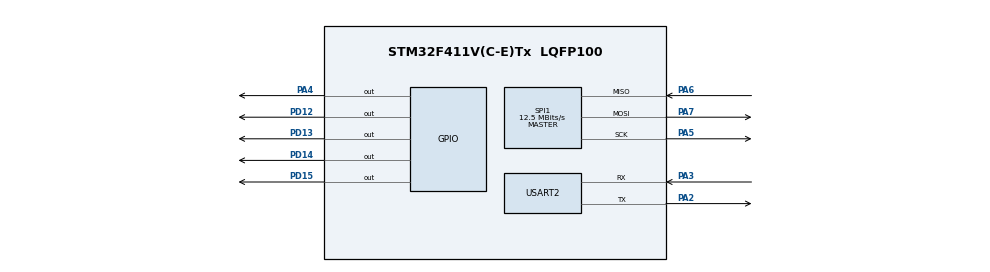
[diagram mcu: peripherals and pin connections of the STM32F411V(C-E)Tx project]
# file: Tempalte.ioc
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Mcu.Family=STM32F4
Mcu.Name=STM32F411V(C-E)Tx
Mcu.Package=LQFP100
NVIC.PriorityGroup=NVIC_PRIORITYGROUP_4
PA2.Mode=Asynchronous
PA2.Signal=USART2_TX
PA3.Mode=Asynchronous
PA3.Signal=USART2_RX
PA4.Signal=GPIO_Output
PA5.Mode=Full_Duplex_Master
PA5.Signal=SPI1_SCK
PA6.Mode=Full_Duplex_Master
PA6.Signal=SPI1_MISO
PA7.Mode=Full_Duplex_Master
PA7.Signal=SPI1_MOSI
PD12.Signal=GPIO_Output
PD13.Signal=GPIO_Output
PD14.Signal=GPIO_Output
PD15.Signal=GPIO_Output
PH0\ -\ OSC_IN.Mode=HSE-External-Oscillator
PH0\ -\ OSC_IN.Signal=RCC_OSC_IN
PH1\ -\ OSC_OUT.Mode=HSE-External-Oscillator
PH1\ -\ OSC_OUT.Signal=RCC_OSC_OUT
ProjectManager.HeapSize=0x200
ProjectManager.StackSize=0x400
ProjectManager.TargetToolchain=Makefile
RCC.AHBFreq_Value=25000000
RCC.APB1Freq_Value=25000000
RCC.APB1TimFreq_Value=25000000
RCC.APB2Freq_Value=25000000
RCC.APB2TimFreq_Value=25000000
RCC.CortexFreq_Value=25000000
RCC.HCLKFreq_Value=25000000
RCC.HSE_VALUE=25000000
RCC.HSI_VALUE=16000000
RCC.LSE_VALUE=32768
RCC.SYSCLKFreq_VALUE=25000000
RCC.SYSCLKSource=RCC_SYSCLKSOURCE_HSE
RCC.VCOOutputFreq_Value=192000000
SPI1.CalculateBaudRate=12.5 MBits/s
SPI1.Direction=SPI_DIRECTION_2LINES
SPI1.Mode=SPI_MODE_MASTER
SPI1.VirtualType=VM_MASTER
USART2.VirtualMode=VM_ASYNC
board=custom

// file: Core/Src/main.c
/* USER CODE BEGIN Header */
/**
  ******************************************************************************
  * @file           : main.c
  * @brief          : STM32F411 Discovery Onboard Gyroscope SPI1 Test
  ******************************************************************************
  */
/* USER CODE END Header */

#include "main.h"
#include "stdlib.h"

SPI_HandleTypeDef hspi1;
UART_HandleTypeDef huart2;

/* Macro điều khiển chân Chip Select (CS) của Gyro onboard (PE3) */
#define TEST 1

void SystemClock_Config(void);
static void MX_GPIO_Init(void);
static void MX_SPI1_Init(void);
static void MX_USART2_UART_Init(void);

void UART_PrintChar(char c);
void UART_PrintStr(const char *str);
void UART_PrintHex(uint8_t num);

uint8_t flag_exti0 = 0;
volatile uint16_t exti_pin = 0;
uint8_t  flag_exti = 0;

void EXTI0_IRQHandler(void) {

   HAL_GPIO_EXTI_IRQHandler(GPIO_PIN_0);
   UART_PrintStr("\r\n=======EXTI0_IRQHandler Complete=======\r\n");
   UART_PrintStr("\r\n=======Flag = {");
   UART_PrintChar(flag_exti0);
   UART_PrintStr("}---\r\n");

}

void HAL_GPIO_EXTI_Callback(uint16_t GPIO_Pin)
{
  UNUSED(GPIO_Pin);

  exti_pin  = GPIO_Pin;
  flag_exti = 1;
  if (GPIO_Pin == GPIO_PIN_0) {
      if(!flag_exti0)
        flag_exti0 = 1;
  }

}

void Init_EXTI0_ButtonUser(void) {
  GPIO_InitTypeDef gpio = {0};
  __HAL_RCC_GPIOA_CLK_ENABLE();
  gpio.Mode = GPIO_MODE_IT_RISING;
  gpio.Pull = GPIO_NOPULL;

  gpio.Pin = GPIO_PIN_0;                 // Discovery / Black Pill
  HAL_GPIO_Init(GPIOA, &gpio);

  HAL_NVIC_SetPriority(EXTI0_IRQn, 2, 0);
  HAL_NVIC_EnableIRQ(EXTI0_IRQn);
}

void SPI1_IRQHandler(void) {
  HAL_SPI_IRQHandler(&hspi1);
}

void HAL_SPI_ErrorCallback(SPI_HandleTypeDef *hspi) {
  UART_PrintStr("\r\n=======SPI ERROR=======\r\n");
}

static void DumpClockSystemAndSyTick() {

  printf("Clock System = %d\n", SystemCoreClock);
  printf("Frequence of systick = ");
  switch (HAL_GetTickFreq())
  {
  case HAL_TICK_FREQ_10HZ:
    printf("10HZ => T = 0,1s \n");
    break;
  case HAL_TICK_FREQ_100HZ:
    printf("100HZ => T = 0,01s \n");
    break;
  case HAL_TICK_FREQ_1KHZ:
    printf("1000HZ => T = 1ms \n");
    break;
  default:
    break;
  }
}

int main(void)
{
  /* Khởi tạo hệ thống HAL, Clock và Peripherals */
  HAL_Init();
  SystemClock_Config();
  MX_GPIO_Init();
  MX_SPI1_Init();
  MX_USART2_UART_Init();
  HAL_Delay(200);
  Init_EXTI0_ButtonUser();
  UART_PrintStr("\033[2J\033[H"); // Clear terminal

  UART_PrintStr("\r\n==================================\r\n");
  UART_PrintStr("  STM32F411 INIT    \r\n");
  UART_PrintStr("==================================\r\n");
  DumpClockSystemAndSyTick();
  uint16_t current_tick = HAL_GetTick();
  printf("First Systick = %d\n", current_tick);
  while (HAL_GetTick() - current_tick < 1000);
  printf("End Systick = %d\n", HAL_GetTick());

  UART_PrintStr("\r\n==================================\r\n");
  UART_PrintStr("  STM32F411 DISCOVERY SPI TEST    \r\n");
  UART_PrintStr("==================================\r\n");

#if(TEST)
  Read_Gyro_WHO_AM_I();
  TC_Write_Single_mode_CTRL_REG3_22H();
  TC_Write_Mul_Mode_CTRL_REG1_20H_21H();
  TC_Read_Mul_Mode_CTRL_REG1_20H_21H();
#endif
  /* Vòng lặp chính */
  int count = 10U;
  while (1)
  {

  }
}

void SystemClock_Config(void)
{
  RCC_OscInitTypeDef RCC_OscInitStruct = {0};
  RCC_ClkInitTypeDef RCC_ClkInitStruct = {0};

  __HAL_RCC_PWR_CLK_ENABLE();
  __HAL_PWR_VOLTAGESCALING_CONFIG(PWR_REGULATOR_VOLTAGE_SCALE1);

  RCC_OscInitStruct.OscillatorType = RCC_OSCILLATORTYPE_HSI;
  RCC_OscInitStruct.HSIState = RCC_HSI_ON;
  RCC_OscInitStruct.HSICalibrationValue = RCC_HSICALIBRATION_DEFAULT;
  RCC_OscInitStruct.PLL.PLLState = RCC_PLL_NONE;
  if (HAL_RCC_OscConfig(&RCC_OscInitStruct) != HAL_OK)
  {
    Error_Handler();
  }

  RCC_ClkInitStruct.ClockType = RCC_CLOCKTYPE_HCLK | RCC_CLOCKTYPE_SYSCLK
                              | RCC_CLOCKTYPE_PCLK1 | RCC_CLOCKTYPE_PCLK2;
  RCC_ClkInitStruct.SYSCLKSource = RCC_SYSCLKSOURCE_HSI;
  RCC_ClkInitStruct.AHBCLKDivider = RCC_SYSCLK_DIV1;
  RCC_ClkInitStruct.APB1CLKDivider = RCC_HCLK_DIV1;
  RCC_ClkInitStruct.APB2CLKDivider = RCC_HCLK_DIV1;

  if (HAL_RCC_ClockConfig(&RCC_ClkInitStruct, FLASH_LATENCY_0) != HAL_OK)
  {
    Error_Handler();
  }
}

static void MX_SPI1_Init(void)
{
  __HAL_RCC_SPI1_CLK_ENABLE();

  hspi1.Instance = SPI1;
  hspi1.Init.Mode = SPI_MODE_MASTER;
  hspi1.Init.Direction = SPI_DIRECTION_2LINES;
  hspi1.Init.DataSize = SPI_DATASIZE_8BIT;

  /* Cấu hình SPI Mode 3 (CPOL High, CPHA 2Edge) cho L3GD20 */
  hspi1.Init.CLKPolarity = SPI_POLARITY_HIGH;
  hspi1.Init.CLKPhase = SPI_PHASE_2EDGE;

  hspi1.Init.NSS = SPI_NSS_SOFT;
  hspi1.Init.BaudRatePrescaler = SPI_BAUDRATEPRESCALER_8; // Baudrate ~2MHz
  hspi1.Init.FirstBit = SPI_FIRSTBIT_MSB;
  hspi1.Init.TIMode = SPI_TIMODE_DISABLE;
  hspi1.Init.CRCCalculation = SPI_CRCCALCULATION_DISABLE;
  hspi1.Init.CRCPolynomial = 10;

  if (HAL_SPI_Init(&hspi1) != HAL_OK)
  {
    Error_Handler();
  }

  HAL_NVIC_SetPriority(SPI1_IRQn, 3, 0);
  HAL_NVIC_EnableIRQ(SPI1_IRQn);
}

static void MX_USART2_UART_Init(void)
{
  __HAL_RCC_USART2_CLK_ENABLE();

  huart2.Instance = USART2;
  huart2.Init.BaudRate = 115200;
  huart2.Init.WordLength = UART_WORDLENGTH_8B;
  huart2.Init.StopBits = UART_STOPBITS_1;
  huart2.Init.Parity = UART_PARITY_NONE;
  huart2.Init.Mode = UART_MODE_TX_RX;
  huart2.Init.HwFlowCtl = UART_HWCONTROL_NONE;
  huart2.Init.OverSampling = UART_OVERSAMPLING_16;

  if (HAL_UART_Init(&huart2) != HAL_OK)
  {
    Error_Handler();
  }
}

static void MX_GPIO_Init(void)
{
  GPIO_InitTypeDef GPIO_InitStruct = {0};

  /* Bật Clock cho các Port GPIO cần thiết */
  __HAL_RCC_GPIOA_CLK_ENABLE();
  __HAL_RCC_GPIOD_CLK_ENABLE();
  __HAL_RCC_GPIOE_CLK_ENABLE();

  /* 1. Cấu hình PE3: Chip Select (CS) cho Gyro Onboard */
  HAL_GPIO_WritePin(GPIOE, GPIO_PIN_3, GPIO_PIN_SET); // Mặc định HIGH (De-select)
  GPIO_InitStruct.Pin = GPIO_PIN_3;
  GPIO_InitStruct.Mode = GPIO_MODE_OUTPUT_PP;
  GPIO_InitStruct.Pull = GPIO_NOPULL;
  GPIO_InitStruct.Speed = GPIO_SPEED_FREQ_VERY_HIGH;
  HAL_GPIO_Init(GPIOE, &GPIO_InitStruct);

  /* 2. Cấu hình PD12: LED Green chỉ báo trạng thái */
  HAL_GPIO_WritePin(GPIOD, GPIO_PIN_12, GPIO_PIN_RESET);
  GPIO_InitStruct.Pin = GPIO_PIN_12;
  GPIO_InitStruct.Mode = GPIO_MODE_OUTPUT_PP;
  GPIO_InitStruct.Pull = GPIO_NOPULL;
  GPIO_InitStruct.Speed = GPIO_SPEED_FREQ_LOW;
  HAL_GPIO_Init(GPIOD, &GPIO_InitStruct);

  /* 3. Cấu hình PA2 (TX), PA3 (RX): USART2 Alternate Function */
  GPIO_InitStruct.Pin = GPIO_PIN_2 | GPIO_PIN_3;
  GPIO_InitStruct.Mode = GPIO_MODE_AF_PP;
  GPIO_InitStruct.Pull = GPIO_PULLUP;
  GPIO_InitStruct.Speed = GPIO_SPEED_FREQ_VERY_HIGH;
  GPIO_InitStruct.Alternate = GPIO_AF7_USART2;
  HAL_GPIO_Init(GPIOA, &GPIO_InitStruct);

  /* 4. Cấu hình PA5 (SCK), PA6 (MISO), PA7 (MOSI): SPI1 Alternate Function */
  GPIO_InitStruct.Pin = GPIO_PIN_5 | GPIO_PIN_6 | GPIO_PIN_7;
  GPIO_InitStruct.Mode = GPIO_MODE_AF_PP;
  GPIO_InitStruct.Pull = GPIO_NOPULL;
  GPIO_InitStruct.Speed = GPIO_SPEED_FREQ_VERY_HIGH;
  GPIO_InitStruct.Alternate = GPIO_AF5_SPI1;
  HAL_GPIO_Init(GPIOA, &GPIO_InitStruct);
}

void Error_Handler(void)
{
  __disable_irq();
  while (1)
  {
  }
}
